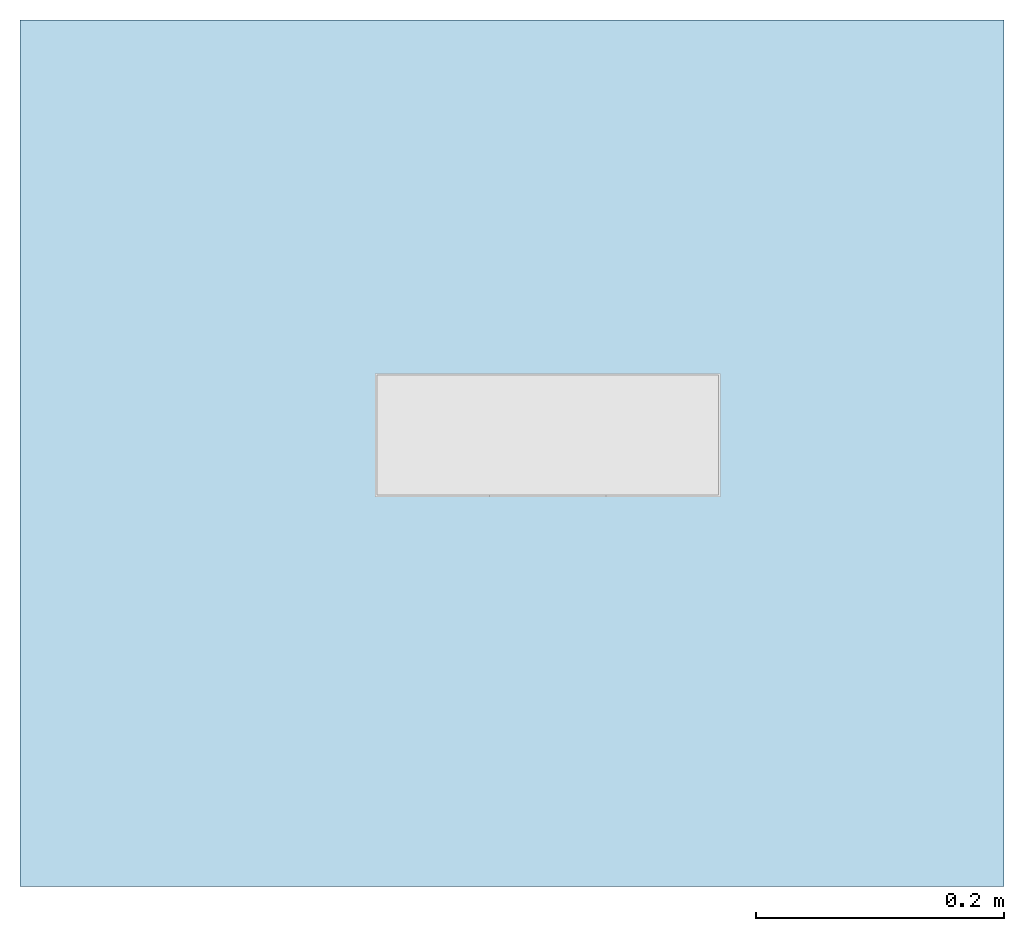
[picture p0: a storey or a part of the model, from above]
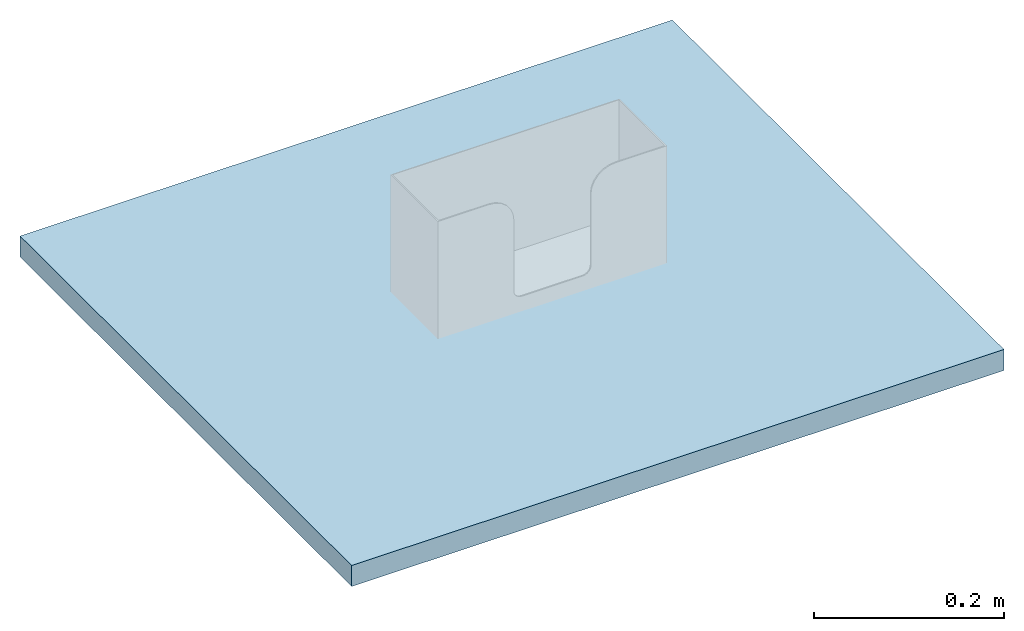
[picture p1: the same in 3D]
Properties of the parts of a building model (IFC2X3)

# File
Description: ViewDefinition [CoordinationView]
Time: 2017-10-03T14:02:41
Written by: The EXPRESS Data Manager Version 5.01.0100.02.64mod : 6 Jun 2012
Made in: 20140709_2115(x64) - Exporter 2014.0.2014.0709 - Default UI
Comment: STEP Physical File produced by: The EXPRESS Data Manager Version 5.01.0100.02.64mod : 6 Jun 2012 * Module: EDMstepFileFactory/EDMstandAlone * Creation date: Tue Oct 03 14:02:41 2017 * Host: BIM-HP * Database: C:\Users\dcole\AppData\Local\Temp\{03887232-8502-4B63-94B0-2440CCECC806}\ifc * Database version: 5507 * Database creation date: Tue Oct 03 14:02:39 2017 * Schema: IFC2X3 * Model: DataRepository.ifc * Model creation date: Tue Oct 03 14:02:39 2017 * Header model: DataRepository.ifc_HeaderModel * Header model creation date: Tue Oct 03 14:02:39 2017 * EDMuser: sdai-user * EDMgroup: sdai-group * License ID and type: 5605 : Permanent license. Expiry date: * EDMstepFileFactory options: 020000

# IfcProject
LongName: P:\Fastrack\53721_BELL-CHEM\ADDITIONAL DRAWINGS 2017 BIM\IFC\BC919.ifc

# IfcSite, Default
RefLatitude: 42, 24, 53, 508911; RefLongitude: -71, -15, -29, -58837; RefElevation: 0 mm

# IfcBuilding
Pset_BuildingCommon - NumberOfStoreys: 1

# IfcBuildingStorey, Level 1
LongName: Level 1; Elevation: 0 mm
Graphics - Symbol at End 2 Default: yes; Line Pattern: -3000010; Symbol at End 1 Default: no; Line Weight: 1; Color: 0
Identity Data - Building Story: yes; Name: Level 1; Structural: no
Dimensions - Computation Height: 0 mm
Constraints - Elevation: 0 mm; Elevation Base: Project Base Point

# IfcBuildingElementProxy: BC919 Dolphin Paper Towel Dispenser, BC919:BC919 Dolphin Paper Towel Dispenser:41743
In: Level 1
Dimensions - Volume: 0.000205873 m3; Capacity Paper Towels: 150 paper towels; Projection: 100mm; Width: 297mm; Height: 152mm
Constraints - Offset: 0 mm; Host: Floor : Counter; Moves With Nearby Elements: no; Level: Level: Level 1
Phasing - Phase Created: New Construction
Pset_ManufacturerTypeInformation - Manufacturer: Dolphin Solutions Limited
Pset_BuildingElementProxyCommon - Reference: BC919 Dolphin Paper Towel Dispenser
Identity Data - Tel No.: +44 (0) 1424 202224; Assembly Code: D2010900; Assembly Description: Other Plumbing Fixtures; Email: info@dolphinsolutions.co.uk; Address: Southpoint, Compass Park, Bodiam, Robertsbridge, TN32 5BS; URL: www.dolphinsolutions.co.uk; Manufacturer: Dolphin Solutions Limited; Description: Paper Towel Dispenser; Model: BC919; Fax No.: +44 (0) 1424 205200
General - Product Data: High quality 304 stainless steel. Satin finish, welded corners - no sharp edges. Capacity for 150 paper towels. Fee standing dispenser - that can be fixed to counter top via screw holes in the base; Product Page Link: www.dolphinsolutions.co.uk/product/paper-towel-dispenser-2

# IfcSlab: Floor:Counter, Floor:Counter:2279
In: Level 1
PredefinedType: FLOOR; Material: Analytical Floor Surface 27 mm
Dimensions - Area: 0.5565 m2; Thickness: 27 mm; Perimeter: 2990 mm; Volume: 0.0150255 m3
Constraints - Height Offset From Level: 0 mm; Related to Mass: no; Room Bounding: yes; Level: Level: Level 1
Structural - Enable Analytical Model: no; Structural: no
Phasing - Phase Created: New Construction
Pset_SlabCommon - Reference: Counter; IsExternal: no; LoadBearing: yes; PitchAngle: 0 deg
Construction - Default Thickness: 27 mm
Analytical Properties - Absorptance: 0.1; Roughness: 1
Graphics - Coarse Scale Fill Color: 8454143; Coarse Scale Fill Pattern: Solid fill
